VERSION 5.8 ;
BUSBITCHARS "[]" ;
DIVIDERCHAR "/" ;
UNITS
  DATABASE MICRONS 1000 ;
END UNITS
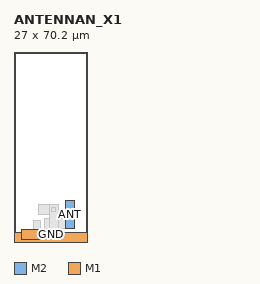
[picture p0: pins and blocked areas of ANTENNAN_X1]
MACRO ANTENNAN_X1
  CLASS CORE ANTENNACELL ;
  ORIGIN 0 0 ;
  SIZE 27.000 BY 70.200 ;
  SYMMETRY X ;
  SITE TR10_access_site ;
  PIN ANT
    DIRECTION INPUT ;
    USE SIGNAL ;
    ANTENNADIFFAREA 9.520 ;
    PORT
      LAYER M2 ;
        RECT 18.900 5.100 22.300 15.400 ;
    END
  END ANT
  PIN GND
    DIRECTION INOUT ;
    USE GROUND ;
    PORT
      LAYER M1 ;
        RECT 0.000 0.000 27.000 3.400 ;
        RECT 2.700 1.100 9.800 4.500 ;
    END
  END GND
  OBS
    LAYER M1 ;
      RECT 7.200 4.500 9.800 8.100 ;
      RECT 9.200 10.300 16.400 13.700 ;
      RECT 11.200 5.100 22.300 8.500 ;
    LAYER M2 ;
      RECT 5.400 1.100 16.400 4.500 ;
      RECT 13.000 1.100 16.400 13.700 ;
    LAYER V1 ;
      RECT 6.400 2.100 7.800 3.500 ;
      RECT 14.000 11.300 15.400 12.700 ;
      RECT 19.900 6.100 21.300 7.500 ;
  END
END ANTENNAN_X1
END LIBRARY
